VERSION 5.7 ;
BUSBITCHARS "[]" ;
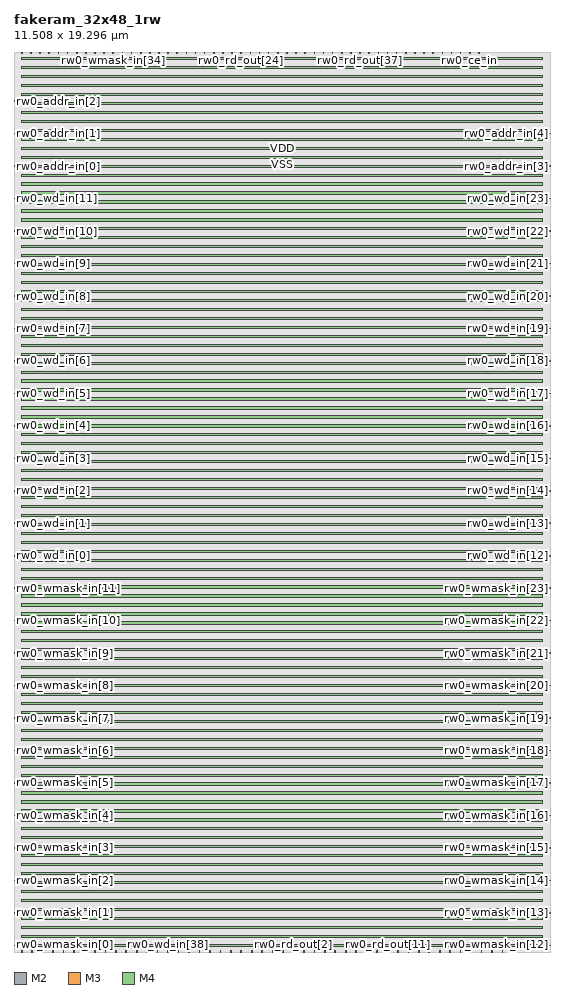
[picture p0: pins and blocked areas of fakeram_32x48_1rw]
MACRO fakeram_32x48_1rw
  FOREIGN fakeram_32x48_1rw 0 0 ;
  SYMMETRY X Y R90 ;
  SIZE 11.508 BY 19.296 ;
  CLASS BLOCK ;
  PIN rw0_wmask_in[0]
    DIRECTION INPUT ;
    USE SIGNAL ;
    SHAPE ABUTMENT ;
    PORT
      LAYER M2 ;
      RECT 0.000 0.138 0.036 0.150 ;
    END
  END rw0_wmask_in[0]
  PIN rw0_wmask_in[1]
    DIRECTION INPUT ;
    USE SIGNAL ;
    SHAPE ABUTMENT ;
    PORT
      LAYER M2 ;
      RECT 0.000 0.834 0.036 0.846 ;
    END
  END rw0_wmask_in[1]
  PIN rw0_wmask_in[2]
    DIRECTION INPUT ;
    USE SIGNAL ;
    SHAPE ABUTMENT ;
    PORT
      LAYER M2 ;
      RECT 0.000 1.530 0.036 1.542 ;
    END
  END rw0_wmask_in[2]
  PIN rw0_wmask_in[3]
    DIRECTION INPUT ;
    USE SIGNAL ;
    SHAPE ABUTMENT ;
    PORT
      LAYER M2 ;
      RECT 0.000 2.226 0.036 2.238 ;
    END
  END rw0_wmask_in[3]
  PIN rw0_wmask_in[4]
    DIRECTION INPUT ;
    USE SIGNAL ;
    SHAPE ABUTMENT ;
    PORT
      LAYER M2 ;
      RECT 0.000 2.922 0.036 2.934 ;
    END
  END rw0_wmask_in[4]
  PIN rw0_wmask_in[5]
    DIRECTION INPUT ;
    USE SIGNAL ;
    SHAPE ABUTMENT ;
    PORT
      LAYER M2 ;
      RECT 0.000 3.618 0.036 3.630 ;
    END
  END rw0_wmask_in[5]
  PIN rw0_wmask_in[6]
    DIRECTION INPUT ;
    USE SIGNAL ;
    SHAPE ABUTMENT ;
    PORT
      LAYER M2 ;
      RECT 0.000 4.314 0.036 4.326 ;
    END
  END rw0_wmask_in[6]
  PIN rw0_wmask_in[7]
    DIRECTION INPUT ;
    USE SIGNAL ;
    SHAPE ABUTMENT ;
    PORT
      LAYER M2 ;
      RECT 0.000 5.010 0.036 5.022 ;
    END
  END rw0_wmask_in[7]
  PIN rw0_wmask_in[8]
    DIRECTION INPUT ;
    USE SIGNAL ;
    SHAPE ABUTMENT ;
    PORT
      LAYER M2 ;
      RECT 0.000 5.706 0.036 5.718 ;
    END
  END rw0_wmask_in[8]
  PIN rw0_wmask_in[9]
    DIRECTION INPUT ;
    USE SIGNAL ;
    SHAPE ABUTMENT ;
    PORT
      LAYER M2 ;
      RECT 0.000 6.402 0.036 6.414 ;
    END
  END rw0_wmask_in[9]
  PIN rw0_wmask_in[10]
    DIRECTION INPUT ;
    USE SIGNAL ;
    SHAPE ABUTMENT ;
    PORT
      LAYER M2 ;
      RECT 0.000 7.098 0.036 7.110 ;
    END
  END rw0_wmask_in[10]
  PIN rw0_wmask_in[11]
    DIRECTION INPUT ;
    USE SIGNAL ;
    SHAPE ABUTMENT ;
    PORT
      LAYER M2 ;
      RECT 0.000 7.794 0.036 7.806 ;
    END
  END rw0_wmask_in[11]
  PIN rw0_wmask_in[12]
    DIRECTION INPUT ;
    USE SIGNAL ;
    SHAPE ABUTMENT ;
    PORT
      LAYER M2 ;
      RECT 11.472 0.138 11.508 0.150 ;
    END
  END rw0_wmask_in[12]
  PIN rw0_wmask_in[13]
    DIRECTION INPUT ;
    USE SIGNAL ;
    SHAPE ABUTMENT ;
    PORT
      LAYER M2 ;
      RECT 11.472 0.834 11.508 0.846 ;
    END
  END rw0_wmask_in[13]
  PIN rw0_wmask_in[14]
    DIRECTION INPUT ;
    USE SIGNAL ;
    SHAPE ABUTMENT ;
    PORT
      LAYER M2 ;
      RECT 11.472 1.530 11.508 1.542 ;
    END
  END rw0_wmask_in[14]
  PIN rw0_wmask_in[15]
    DIRECTION INPUT ;
    USE SIGNAL ;
    SHAPE ABUTMENT ;
    PORT
      LAYER M2 ;
      RECT 11.472 2.226 11.508 2.238 ;
    END
  END rw0_wmask_in[15]
  PIN rw0_wmask_in[16]
    DIRECTION INPUT ;
    USE SIGNAL ;
    SHAPE ABUTMENT ;
    PORT
      LAYER M2 ;
      RECT 11.472 2.922 11.508 2.934 ;
    END
  END rw0_wmask_in[16]
  PIN rw0_wmask_in[17]
    DIRECTION INPUT ;
    USE SIGNAL ;
    SHAPE ABUTMENT ;
    PORT
      LAYER M2 ;
      RECT 11.472 3.618 11.508 3.630 ;
    END
  END rw0_wmask_in[17]
  PIN rw0_wmask_in[18]
    DIRECTION INPUT ;
    USE SIGNAL ;
    SHAPE ABUTMENT ;
    PORT
      LAYER M2 ;
      RECT 11.472 4.314 11.508 4.326 ;
    END
  END rw0_wmask_in[18]
  PIN rw0_wmask_in[19]
    DIRECTION INPUT ;
    USE SIGNAL ;
    SHAPE ABUTMENT ;
    PORT
      LAYER M2 ;
      RECT 11.472 5.010 11.508 5.022 ;
    END
  END rw0_wmask_in[19]
  PIN rw0_wmask_in[20]
    DIRECTION INPUT ;
    USE SIGNAL ;
    SHAPE ABUTMENT ;
    PORT
      LAYER M2 ;
      RECT 11.472 5.706 11.508 5.718 ;
    END
  END rw0_wmask_in[20]
  PIN rw0_wmask_in[21]
    DIRECTION INPUT ;
    USE SIGNAL ;
    SHAPE ABUTMENT ;
    PORT
      LAYER M2 ;
      RECT 11.472 6.402 11.508 6.414 ;
    END
  END rw0_wmask_in[21]
  PIN rw0_wmask_in[22]
    DIRECTION INPUT ;
    USE SIGNAL ;
    SHAPE ABUTMENT ;
    PORT
      LAYER M2 ;
      RECT 11.472 7.098 11.508 7.110 ;
    END
  END rw0_wmask_in[22]
  PIN rw0_wmask_in[23]
    DIRECTION INPUT ;
    USE SIGNAL ;
    SHAPE ABUTMENT ;
    PORT
      LAYER M2 ;
      RECT 11.472 7.794 11.508 7.806 ;
    END
  END rw0_wmask_in[23]
  PIN rw0_wmask_in[24]
    DIRECTION INPUT ;
    USE SIGNAL ;
    SHAPE ABUTMENT ;
    PORT
      LAYER M3 ;
      RECT 0.161 19.254 0.175 19.296 ;
    END
  END rw0_wmask_in[24]
  PIN rw0_wmask_in[25]
    DIRECTION INPUT ;
    USE SIGNAL ;
    SHAPE ABUTMENT ;
    PORT
      LAYER M3 ;
      RECT 0.357 19.254 0.371 19.296 ;
    END
  END rw0_wmask_in[25]
  PIN rw0_wmask_in[26]
    DIRECTION INPUT ;
    USE SIGNAL ;
    SHAPE ABUTMENT ;
    PORT
      LAYER M3 ;
      RECT 0.553 19.254 0.567 19.296 ;
    END
  END rw0_wmask_in[26]
  PIN rw0_wmask_in[27]
    DIRECTION INPUT ;
    USE SIGNAL ;
    SHAPE ABUTMENT ;
    PORT
      LAYER M3 ;
      RECT 0.749 19.254 0.763 19.296 ;
    END
  END rw0_wmask_in[27]
  PIN rw0_wmask_in[28]
    DIRECTION INPUT ;
    USE SIGNAL ;
    SHAPE ABUTMENT ;
    PORT
      LAYER M3 ;
      RECT 0.945 19.254 0.959 19.296 ;
    END
  END rw0_wmask_in[28]
  PIN rw0_wmask_in[29]
    DIRECTION INPUT ;
    USE SIGNAL ;
    SHAPE ABUTMENT ;
    PORT
      LAYER M3 ;
      RECT 1.141 19.254 1.155 19.296 ;
    END
  END rw0_wmask_in[29]
  PIN rw0_wmask_in[30]
    DIRECTION INPUT ;
    USE SIGNAL ;
    SHAPE ABUTMENT ;
    PORT
      LAYER M3 ;
      RECT 1.337 19.254 1.351 19.296 ;
    END
  END rw0_wmask_in[30]
  PIN rw0_wmask_in[31]
    DIRECTION INPUT ;
    USE SIGNAL ;
    SHAPE ABUTMENT ;
    PORT
      LAYER M3 ;
      RECT 1.533 19.254 1.547 19.296 ;
    END
  END rw0_wmask_in[31]
  PIN rw0_wmask_in[32]
    DIRECTION INPUT ;
    USE SIGNAL ;
    SHAPE ABUTMENT ;
    PORT
      LAYER M3 ;
      RECT 1.729 19.254 1.743 19.296 ;
    END
  END rw0_wmask_in[32]
  PIN rw0_wmask_in[33]
    DIRECTION INPUT ;
    USE SIGNAL ;
    SHAPE ABUTMENT ;
    PORT
      LAYER M3 ;
      RECT 1.925 19.254 1.939 19.296 ;
    END
  END rw0_wmask_in[33]
  PIN rw0_wmask_in[34]
    DIRECTION INPUT ;
    USE SIGNAL ;
    SHAPE ABUTMENT ;
    PORT
      LAYER M3 ;
      RECT 2.121 19.254 2.135 19.296 ;
    END
  END rw0_wmask_in[34]
  PIN rw0_wmask_in[35]
    DIRECTION INPUT ;
    USE SIGNAL ;
    SHAPE ABUTMENT ;
    PORT
      LAYER M3 ;
      RECT 2.317 19.254 2.331 19.296 ;
    END
  END rw0_wmask_in[35]
  PIN rw0_wmask_in[36]
    DIRECTION INPUT ;
    USE SIGNAL ;
    SHAPE ABUTMENT ;
    PORT
      LAYER M3 ;
      RECT 2.513 19.254 2.527 19.296 ;
    END
  END rw0_wmask_in[36]
  PIN rw0_wmask_in[37]
    DIRECTION INPUT ;
    USE SIGNAL ;
    SHAPE ABUTMENT ;
    PORT
      LAYER M3 ;
      RECT 2.709 19.254 2.723 19.296 ;
    END
  END rw0_wmask_in[37]
  PIN rw0_wmask_in[38]
    DIRECTION INPUT ;
    USE SIGNAL ;
    SHAPE ABUTMENT ;
    PORT
      LAYER M3 ;
      RECT 2.905 19.254 2.919 19.296 ;
    END
  END rw0_wmask_in[38]
  PIN rw0_wmask_in[39]
    DIRECTION INPUT ;
    USE SIGNAL ;
    SHAPE ABUTMENT ;
    PORT
      LAYER M3 ;
      RECT 3.101 19.254 3.115 19.296 ;
    END
  END rw0_wmask_in[39]
  PIN rw0_wmask_in[40]
    DIRECTION INPUT ;
    USE SIGNAL ;
    SHAPE ABUTMENT ;
    PORT
      LAYER M3 ;
      RECT 3.297 19.254 3.311 19.296 ;
    END
  END rw0_wmask_in[40]
  PIN rw0_wmask_in[41]
    DIRECTION INPUT ;
    USE SIGNAL ;
    SHAPE ABUTMENT ;
    PORT
      LAYER M3 ;
      RECT 3.493 19.254 3.507 19.296 ;
    END
  END rw0_wmask_in[41]
  PIN rw0_wmask_in[42]
    DIRECTION INPUT ;
    USE SIGNAL ;
    SHAPE ABUTMENT ;
    PORT
      LAYER M3 ;
      RECT 3.689 19.254 3.703 19.296 ;
    END
  END rw0_wmask_in[42]
  PIN rw0_wmask_in[43]
    DIRECTION INPUT ;
    USE SIGNAL ;
    SHAPE ABUTMENT ;
    PORT
      LAYER M3 ;
      RECT 3.885 19.254 3.899 19.296 ;
    END
  END rw0_wmask_in[43]
  PIN rw0_wmask_in[44]
    DIRECTION INPUT ;
    USE SIGNAL ;
    SHAPE ABUTMENT ;
    PORT
      LAYER M3 ;
      RECT 4.081 19.254 4.095 19.296 ;
    END
  END rw0_wmask_in[44]
  PIN rw0_wmask_in[45]
    DIRECTION INPUT ;
    USE SIGNAL ;
    SHAPE ABUTMENT ;
    PORT
      LAYER M3 ;
      RECT 4.277 19.254 4.291 19.296 ;
    END
  END rw0_wmask_in[45]
  PIN rw0_wmask_in[46]
    DIRECTION INPUT ;
    USE SIGNAL ;
    SHAPE ABUTMENT ;
    PORT
      LAYER M3 ;
      RECT 4.473 19.254 4.487 19.296 ;
    END
  END rw0_wmask_in[46]
  PIN rw0_wmask_in[47]
    DIRECTION INPUT ;
    USE SIGNAL ;
    SHAPE ABUTMENT ;
    PORT
      LAYER M3 ;
      RECT 4.669 19.254 4.683 19.296 ;
    END
  END rw0_wmask_in[47]
  PIN rw0_wd_in[0]
    DIRECTION INPUT ;
    USE SIGNAL ;
    SHAPE ABUTMENT ;
    PORT
      LAYER M2 ;
      RECT 0.000 8.490 0.036 8.502 ;
    END
  END rw0_wd_in[0]
  PIN rw0_wd_in[1]
    DIRECTION INPUT ;
    USE SIGNAL ;
    SHAPE ABUTMENT ;
    PORT
      LAYER M2 ;
      RECT 0.000 9.186 0.036 9.198 ;
    END
  END rw0_wd_in[1]
  PIN rw0_wd_in[2]
    DIRECTION INPUT ;
    USE SIGNAL ;
    SHAPE ABUTMENT ;
    PORT
      LAYER M2 ;
      RECT 0.000 9.882 0.036 9.894 ;
    END
  END rw0_wd_in[2]
  PIN rw0_wd_in[3]
    DIRECTION INPUT ;
    USE SIGNAL ;
    SHAPE ABUTMENT ;
    PORT
      LAYER M2 ;
      RECT 0.000 10.578 0.036 10.590 ;
    END
  END rw0_wd_in[3]
  PIN rw0_wd_in[4]
    DIRECTION INPUT ;
    USE SIGNAL ;
    SHAPE ABUTMENT ;
    PORT
      LAYER M2 ;
      RECT 0.000 11.274 0.036 11.286 ;
    END
  END rw0_wd_in[4]
  PIN rw0_wd_in[5]
    DIRECTION INPUT ;
    USE SIGNAL ;
    SHAPE ABUTMENT ;
    PORT
      LAYER M2 ;
      RECT 0.000 11.970 0.036 11.982 ;
    END
  END rw0_wd_in[5]
  PIN rw0_wd_in[6]
    DIRECTION INPUT ;
    USE SIGNAL ;
    SHAPE ABUTMENT ;
    PORT
      LAYER M2 ;
      RECT 0.000 12.666 0.036 12.678 ;
    END
  END rw0_wd_in[6]
  PIN rw0_wd_in[7]
    DIRECTION INPUT ;
    USE SIGNAL ;
    SHAPE ABUTMENT ;
    PORT
      LAYER M2 ;
      RECT 0.000 13.362 0.036 13.374 ;
    END
  END rw0_wd_in[7]
  PIN rw0_wd_in[8]
    DIRECTION INPUT ;
    USE SIGNAL ;
    SHAPE ABUTMENT ;
    PORT
      LAYER M2 ;
      RECT 0.000 14.058 0.036 14.070 ;
    END
  END rw0_wd_in[8]
  PIN rw0_wd_in[9]
    DIRECTION INPUT ;
    USE SIGNAL ;
    SHAPE ABUTMENT ;
    PORT
      LAYER M2 ;
      RECT 0.000 14.754 0.036 14.766 ;
    END
  END rw0_wd_in[9]
  PIN rw0_wd_in[10]
    DIRECTION INPUT ;
    USE SIGNAL ;
    SHAPE ABUTMENT ;
    PORT
      LAYER M2 ;
      RECT 0.000 15.450 0.036 15.462 ;
    END
  END rw0_wd_in[10]
  PIN rw0_wd_in[11]
    DIRECTION INPUT ;
    USE SIGNAL ;
    SHAPE ABUTMENT ;
    PORT
      LAYER M2 ;
      RECT 0.000 16.146 0.036 16.158 ;
    END
  END rw0_wd_in[11]
  PIN rw0_wd_in[12]
    DIRECTION INPUT ;
    USE SIGNAL ;
    SHAPE ABUTMENT ;
    PORT
      LAYER M2 ;
      RECT 11.472 8.490 11.508 8.502 ;
    END
  END rw0_wd_in[12]
  PIN rw0_wd_in[13]
    DIRECTION INPUT ;
    USE SIGNAL ;
    SHAPE ABUTMENT ;
    PORT
      LAYER M2 ;
      RECT 11.472 9.186 11.508 9.198 ;
    END
  END rw0_wd_in[13]
  PIN rw0_wd_in[14]
    DIRECTION INPUT ;
    USE SIGNAL ;
    SHAPE ABUTMENT ;
    PORT
      LAYER M2 ;
      RECT 11.472 9.882 11.508 9.894 ;
    END
  END rw0_wd_in[14]
  PIN rw0_wd_in[15]
    DIRECTION INPUT ;
    USE SIGNAL ;
    SHAPE ABUTMENT ;
    PORT
      LAYER M2 ;
      RECT 11.472 10.578 11.508 10.590 ;
    END
  END rw0_wd_in[15]
  PIN rw0_wd_in[16]
    DIRECTION INPUT ;
    USE SIGNAL ;
    SHAPE ABUTMENT ;
    PORT
      LAYER M2 ;
      RECT 11.472 11.274 11.508 11.286 ;
    END
  END rw0_wd_in[16]
  PIN rw0_wd_in[17]
    DIRECTION INPUT ;
    USE SIGNAL ;
    SHAPE ABUTMENT ;
    PORT
      LAYER M2 ;
      RECT 11.472 11.970 11.508 11.982 ;
    END
  END rw0_wd_in[17]
  PIN rw0_wd_in[18]
    DIRECTION INPUT ;
    USE SIGNAL ;
    SHAPE ABUTMENT ;
    PORT
      LAYER M2 ;
      RECT 11.472 12.666 11.508 12.678 ;
    END
  END rw0_wd_in[18]
  PIN rw0_wd_in[19]
    DIRECTION INPUT ;
    USE SIGNAL ;
    SHAPE ABUTMENT ;
    PORT
      LAYER M2 ;
      RECT 11.472 13.362 11.508 13.374 ;
    END
  END rw0_wd_in[19]
  PIN rw0_wd_in[20]
    DIRECTION INPUT ;
    USE SIGNAL ;
    SHAPE ABUTMENT ;
    PORT
      LAYER M2 ;
      RECT 11.472 14.058 11.508 14.070 ;
    END
  END rw0_wd_in[20]
  PIN rw0_wd_in[21]
    DIRECTION INPUT ;
    USE SIGNAL ;
    SHAPE ABUTMENT ;
    PORT
      LAYER M2 ;
      RECT 11.472 14.754 11.508 14.766 ;
    END
  END rw0_wd_in[21]
  PIN rw0_wd_in[22]
    DIRECTION INPUT ;
    USE SIGNAL ;
    SHAPE ABUTMENT ;
    PORT
      LAYER M2 ;
      RECT 11.472 15.450 11.508 15.462 ;
    END
  END rw0_wd_in[22]
  PIN rw0_wd_in[23]
    DIRECTION INPUT ;
    USE SIGNAL ;
    SHAPE ABUTMENT ;
    PORT
      LAYER M2 ;
      RECT 11.472 16.146 11.508 16.158 ;
    END
  END rw0_wd_in[23]
  PIN rw0_wd_in[24]
    DIRECTION INPUT ;
    USE SIGNAL ;
    SHAPE ABUTMENT ;
    PORT
      LAYER M3 ;
      RECT 0.161 0.000 0.175 0.042 ;
    END
  END rw0_wd_in[24]
  PIN rw0_wd_in[25]
    DIRECTION INPUT ;
    USE SIGNAL ;
    SHAPE ABUTMENT ;
    PORT
      LAYER M3 ;
      RECT 0.385 0.000 0.399 0.042 ;
    END
  END rw0_wd_in[25]
  PIN rw0_wd_in[26]
    DIRECTION INPUT ;
    USE SIGNAL ;
    SHAPE ABUTMENT ;
    PORT
      LAYER M3 ;
      RECT 0.609 0.000 0.623 0.042 ;
    END
  END rw0_wd_in[26]
  PIN rw0_wd_in[27]
    DIRECTION INPUT ;
    USE SIGNAL ;
    SHAPE ABUTMENT ;
    PORT
      LAYER M3 ;
      RECT 0.833 0.000 0.847 0.042 ;
    END
  END rw0_wd_in[27]
  PIN rw0_wd_in[28]
    DIRECTION INPUT ;
    USE SIGNAL ;
    SHAPE ABUTMENT ;
    PORT
      LAYER M3 ;
      RECT 1.057 0.000 1.071 0.042 ;
    END
  END rw0_wd_in[28]
  PIN rw0_wd_in[29]
    DIRECTION INPUT ;
    USE SIGNAL ;
    SHAPE ABUTMENT ;
    PORT
      LAYER M3 ;
      RECT 1.281 0.000 1.295 0.042 ;
    END
  END rw0_wd_in[29]
  PIN rw0_wd_in[30]
    DIRECTION INPUT ;
    USE SIGNAL ;
    SHAPE ABUTMENT ;
    PORT
      LAYER M3 ;
      RECT 1.505 0.000 1.519 0.042 ;
    END
  END rw0_wd_in[30]
  PIN rw0_wd_in[31]
    DIRECTION INPUT ;
    USE SIGNAL ;
    SHAPE ABUTMENT ;
    PORT
      LAYER M3 ;
      RECT 1.729 0.000 1.743 0.042 ;
    END
  END rw0_wd_in[31]
  PIN rw0_wd_in[32]
    DIRECTION INPUT ;
    USE SIGNAL ;
    SHAPE ABUTMENT ;
    PORT
      LAYER M3 ;
      RECT 1.953 0.000 1.967 0.042 ;
    END
  END rw0_wd_in[32]
  PIN rw0_wd_in[33]
    DIRECTION INPUT ;
    USE SIGNAL ;
    SHAPE ABUTMENT ;
    PORT
      LAYER M3 ;
      RECT 2.177 0.000 2.191 0.042 ;
    END
  END rw0_wd_in[33]
  PIN rw0_wd_in[34]
    DIRECTION INPUT ;
    USE SIGNAL ;
    SHAPE ABUTMENT ;
    PORT
      LAYER M3 ;
      RECT 2.401 0.000 2.415 0.042 ;
    END
  END rw0_wd_in[34]
  PIN rw0_wd_in[35]
    DIRECTION INPUT ;
    USE SIGNAL ;
    SHAPE ABUTMENT ;
    PORT
      LAYER M3 ;
      RECT 2.625 0.000 2.639 0.042 ;
    END
  END rw0_wd_in[35]
  PIN rw0_wd_in[36]
    DIRECTION INPUT ;
    USE SIGNAL ;
    SHAPE ABUTMENT ;
    PORT
      LAYER M3 ;
      RECT 2.849 0.000 2.863 0.042 ;
    END
  END rw0_wd_in[36]
  PIN rw0_wd_in[37]
    DIRECTION INPUT ;
    USE SIGNAL ;
    SHAPE ABUTMENT ;
    PORT
      LAYER M3 ;
      RECT 3.073 0.000 3.087 0.042 ;
    END
  END rw0_wd_in[37]
  PIN rw0_wd_in[38]
    DIRECTION INPUT ;
    USE SIGNAL ;
    SHAPE ABUTMENT ;
    PORT
      LAYER M3 ;
      RECT 3.297 0.000 3.311 0.042 ;
    END
  END rw0_wd_in[38]
  PIN rw0_wd_in[39]
    DIRECTION INPUT ;
    USE SIGNAL ;
    SHAPE ABUTMENT ;
    PORT
      LAYER M3 ;
      RECT 3.521 0.000 3.535 0.042 ;
    END
  END rw0_wd_in[39]
  PIN rw0_wd_in[40]
    DIRECTION INPUT ;
    USE SIGNAL ;
    SHAPE ABUTMENT ;
    PORT
      LAYER M3 ;
      RECT 3.745 0.000 3.759 0.042 ;
    END
  END rw0_wd_in[40]
  PIN rw0_wd_in[41]
    DIRECTION INPUT ;
    USE SIGNAL ;
    SHAPE ABUTMENT ;
    PORT
      LAYER M3 ;
      RECT 3.969 0.000 3.983 0.042 ;
    END
  END rw0_wd_in[41]
  PIN rw0_wd_in[42]
    DIRECTION INPUT ;
    USE SIGNAL ;
    SHAPE ABUTMENT ;
    PORT
      LAYER M3 ;
      RECT 4.193 0.000 4.207 0.042 ;
    END
  END rw0_wd_in[42]
  PIN rw0_wd_in[43]
    DIRECTION INPUT ;
    USE SIGNAL ;
    SHAPE ABUTMENT ;
    PORT
      LAYER M3 ;
      RECT 4.417 0.000 4.431 0.042 ;
    END
  END rw0_wd_in[43]
  PIN rw0_wd_in[44]
    DIRECTION INPUT ;
    USE SIGNAL ;
    SHAPE ABUTMENT ;
    PORT
      LAYER M3 ;
      RECT 4.641 0.000 4.655 0.042 ;
    END
  END rw0_wd_in[44]
  PIN rw0_wd_in[45]
    DIRECTION INPUT ;
    USE SIGNAL ;
    SHAPE ABUTMENT ;
    PORT
      LAYER M3 ;
      RECT 4.865 0.000 4.879 0.042 ;
    END
  END rw0_wd_in[45]
  PIN rw0_wd_in[46]
    DIRECTION INPUT ;
    USE SIGNAL ;
    SHAPE ABUTMENT ;
    PORT
      LAYER M3 ;
      RECT 5.089 0.000 5.103 0.042 ;
    END
  END rw0_wd_in[46]
  PIN rw0_wd_in[47]
    DIRECTION INPUT ;
    USE SIGNAL ;
    SHAPE ABUTMENT ;
    PORT
      LAYER M3 ;
      RECT 5.313 0.000 5.327 0.042 ;
    END
  END rw0_wd_in[47]
  PIN rw0_rd_out[0]
    DIRECTION OUTPUT ;
    USE SIGNAL ;
    SHAPE ABUTMENT ;
    PORT
      LAYER M3 ;
      RECT 5.537 0.000 5.551 0.042 ;
    END
  END rw0_rd_out[0]
  PIN rw0_rd_out[1]
    DIRECTION OUTPUT ;
    USE SIGNAL ;
    SHAPE ABUTMENT ;
    PORT
      LAYER M3 ;
      RECT 5.761 0.000 5.775 0.042 ;
    END
  END rw0_rd_out[1]
  PIN rw0_rd_out[2]
    DIRECTION OUTPUT ;
    USE SIGNAL ;
    SHAPE ABUTMENT ;
    PORT
      LAYER M3 ;
      RECT 5.985 0.000 5.999 0.042 ;
    END
  END rw0_rd_out[2]
  PIN rw0_rd_out[3]
    DIRECTION OUTPUT ;
    USE SIGNAL ;
    SHAPE ABUTMENT ;
    PORT
      LAYER M3 ;
      RECT 6.209 0.000 6.223 0.042 ;
    END
  END rw0_rd_out[3]
  PIN rw0_rd_out[4]
    DIRECTION OUTPUT ;
    USE SIGNAL ;
    SHAPE ABUTMENT ;
    PORT
      LAYER M3 ;
      RECT 6.433 0.000 6.447 0.042 ;
    END
  END rw0_rd_out[4]
  PIN rw0_rd_out[5]
    DIRECTION OUTPUT ;
    USE SIGNAL ;
    SHAPE ABUTMENT ;
    PORT
      LAYER M3 ;
      RECT 6.657 0.000 6.671 0.042 ;
    END
  END rw0_rd_out[5]
  PIN rw0_rd_out[6]
    DIRECTION OUTPUT ;
    USE SIGNAL ;
    SHAPE ABUTMENT ;
    PORT
      LAYER M3 ;
      RECT 6.881 0.000 6.895 0.042 ;
    END
  END rw0_rd_out[6]
  PIN rw0_rd_out[7]
    DIRECTION OUTPUT ;
    USE SIGNAL ;
    SHAPE ABUTMENT ;
    PORT
      LAYER M3 ;
      RECT 7.105 0.000 7.119 0.042 ;
    END
  END rw0_rd_out[7]
  PIN rw0_rd_out[8]
    DIRECTION OUTPUT ;
    USE SIGNAL ;
    SHAPE ABUTMENT ;
    PORT
      LAYER M3 ;
      RECT 7.329 0.000 7.343 0.042 ;
    END
  END rw0_rd_out[8]
  PIN rw0_rd_out[9]
    DIRECTION OUTPUT ;
    USE SIGNAL ;
    SHAPE ABUTMENT ;
    PORT
      LAYER M3 ;
      RECT 7.553 0.000 7.567 0.042 ;
    END
  END rw0_rd_out[9]
  PIN rw0_rd_out[10]
    DIRECTION OUTPUT ;
    USE SIGNAL ;
    SHAPE ABUTMENT ;
    PORT
      LAYER M3 ;
      RECT 7.777 0.000 7.791 0.042 ;
    END
  END rw0_rd_out[10]
  PIN rw0_rd_out[11]
    DIRECTION OUTPUT ;
    USE SIGNAL ;
    SHAPE ABUTMENT ;
    PORT
      LAYER M3 ;
      RECT 8.001 0.000 8.015 0.042 ;
    END
  END rw0_rd_out[11]
  PIN rw0_rd_out[12]
    DIRECTION OUTPUT ;
    USE SIGNAL ;
    SHAPE ABUTMENT ;
    PORT
      LAYER M3 ;
      RECT 8.225 0.000 8.239 0.042 ;
    END
  END rw0_rd_out[12]
  PIN rw0_rd_out[13]
    DIRECTION OUTPUT ;
    USE SIGNAL ;
    SHAPE ABUTMENT ;
    PORT
      LAYER M3 ;
      RECT 8.449 0.000 8.463 0.042 ;
    END
  END rw0_rd_out[13]
  PIN rw0_rd_out[14]
    DIRECTION OUTPUT ;
    USE SIGNAL ;
    SHAPE ABUTMENT ;
    PORT
      LAYER M3 ;
      RECT 8.673 0.000 8.687 0.042 ;
    END
  END rw0_rd_out[14]
  PIN rw0_rd_out[15]
    DIRECTION OUTPUT ;
    USE SIGNAL ;
    SHAPE ABUTMENT ;
    PORT
      LAYER M3 ;
      RECT 8.897 0.000 8.911 0.042 ;
    END
  END rw0_rd_out[15]
  PIN rw0_rd_out[16]
    DIRECTION OUTPUT ;
    USE SIGNAL ;
    SHAPE ABUTMENT ;
    PORT
      LAYER M3 ;
      RECT 9.121 0.000 9.135 0.042 ;
    END
  END rw0_rd_out[16]
  PIN rw0_rd_out[17]
    DIRECTION OUTPUT ;
    USE SIGNAL ;
    SHAPE ABUTMENT ;
    PORT
      LAYER M3 ;
      RECT 9.345 0.000 9.359 0.042 ;
    END
  END rw0_rd_out[17]
  PIN rw0_rd_out[18]
    DIRECTION OUTPUT ;
    USE SIGNAL ;
    SHAPE ABUTMENT ;
    PORT
      LAYER M3 ;
      RECT 9.569 0.000 9.583 0.042 ;
    END
  END rw0_rd_out[18]
  PIN rw0_rd_out[19]
    DIRECTION OUTPUT ;
    USE SIGNAL ;
    SHAPE ABUTMENT ;
    PORT
      LAYER M3 ;
      RECT 9.793 0.000 9.807 0.042 ;
    END
  END rw0_rd_out[19]
  PIN rw0_rd_out[20]
    DIRECTION OUTPUT ;
    USE SIGNAL ;
    SHAPE ABUTMENT ;
    PORT
      LAYER M3 ;
      RECT 10.017 0.000 10.031 0.042 ;
    END
  END rw0_rd_out[20]
  PIN rw0_rd_out[21]
    DIRECTION OUTPUT ;
    USE SIGNAL ;
    SHAPE ABUTMENT ;
    PORT
      LAYER M3 ;
      RECT 10.241 0.000 10.255 0.042 ;
    END
  END rw0_rd_out[21]
  PIN rw0_rd_out[22]
    DIRECTION OUTPUT ;
    USE SIGNAL ;
    SHAPE ABUTMENT ;
    PORT
      LAYER M3 ;
      RECT 10.465 0.000 10.479 0.042 ;
    END
  END rw0_rd_out[22]
  PIN rw0_rd_out[23]
    DIRECTION OUTPUT ;
    USE SIGNAL ;
    SHAPE ABUTMENT ;
    PORT
      LAYER M3 ;
      RECT 10.689 0.000 10.703 0.042 ;
    END
  END rw0_rd_out[23]
  PIN rw0_rd_out[24]
    DIRECTION OUTPUT ;
    USE SIGNAL ;
    SHAPE ABUTMENT ;
    PORT
      LAYER M3 ;
      RECT 4.865 19.254 4.879 19.296 ;
    END
  END rw0_rd_out[24]
  PIN rw0_rd_out[25]
    DIRECTION OUTPUT ;
    USE SIGNAL ;
    SHAPE ABUTMENT ;
    PORT
      LAYER M3 ;
      RECT 5.061 19.254 5.075 19.296 ;
    END
  END rw0_rd_out[25]
  PIN rw0_rd_out[26]
    DIRECTION OUTPUT ;
    USE SIGNAL ;
    SHAPE ABUTMENT ;
    PORT
      LAYER M3 ;
      RECT 5.257 19.254 5.271 19.296 ;
    END
  END rw0_rd_out[26]
  PIN rw0_rd_out[27]
    DIRECTION OUTPUT ;
    USE SIGNAL ;
    SHAPE ABUTMENT ;
    PORT
      LAYER M3 ;
      RECT 5.453 19.254 5.467 19.296 ;
    END
  END rw0_rd_out[27]
  PIN rw0_rd_out[28]
    DIRECTION OUTPUT ;
    USE SIGNAL ;
    SHAPE ABUTMENT ;
    PORT
      LAYER M3 ;
      RECT 5.649 19.254 5.663 19.296 ;
    END
  END rw0_rd_out[28]
  PIN rw0_rd_out[29]
    DIRECTION OUTPUT ;
    USE SIGNAL ;
    SHAPE ABUTMENT ;
    PORT
      LAYER M3 ;
      RECT 5.845 19.254 5.859 19.296 ;
    END
  END rw0_rd_out[29]
  PIN rw0_rd_out[30]
    DIRECTION OUTPUT ;
    USE SIGNAL ;
    SHAPE ABUTMENT ;
    PORT
      LAYER M3 ;
      RECT 6.041 19.254 6.055 19.296 ;
    END
  END rw0_rd_out[30]
  PIN rw0_rd_out[31]
    DIRECTION OUTPUT ;
    USE SIGNAL ;
    SHAPE ABUTMENT ;
    PORT
      LAYER M3 ;
      RECT 6.237 19.254 6.251 19.296 ;
    END
  END rw0_rd_out[31]
  PIN rw0_rd_out[32]
    DIRECTION OUTPUT ;
    USE SIGNAL ;
    SHAPE ABUTMENT ;
    PORT
      LAYER M3 ;
      RECT 6.433 19.254 6.447 19.296 ;
    END
  END rw0_rd_out[32]
  PIN rw0_rd_out[33]
    DIRECTION OUTPUT ;
    USE SIGNAL ;
    SHAPE ABUTMENT ;
    PORT
      LAYER M3 ;
      RECT 6.629 19.254 6.643 19.296 ;
    END
  END rw0_rd_out[33]
  PIN rw0_rd_out[34]
    DIRECTION OUTPUT ;
    USE SIGNAL ;
    SHAPE ABUTMENT ;
    PORT
      LAYER M3 ;
      RECT 6.825 19.254 6.839 19.296 ;
    END
  END rw0_rd_out[34]
  PIN rw0_rd_out[35]
    DIRECTION OUTPUT ;
    USE SIGNAL ;
    SHAPE ABUTMENT ;
    PORT
      LAYER M3 ;
      RECT 7.021 19.254 7.035 19.296 ;
    END
  END rw0_rd_out[35]
  PIN rw0_rd_out[36]
    DIRECTION OUTPUT ;
    USE SIGNAL ;
    SHAPE ABUTMENT ;
    PORT
      LAYER M3 ;
      RECT 7.217 19.254 7.231 19.296 ;
    END
  END rw0_rd_out[36]
  PIN rw0_rd_out[37]
    DIRECTION OUTPUT ;
    USE SIGNAL ;
    SHAPE ABUTMENT ;
    PORT
      LAYER M3 ;
      RECT 7.413 19.254 7.427 19.296 ;
    END
  END rw0_rd_out[37]
  PIN rw0_rd_out[38]
    DIRECTION OUTPUT ;
    USE SIGNAL ;
    SHAPE ABUTMENT ;
    PORT
      LAYER M3 ;
      RECT 7.609 19.254 7.623 19.296 ;
    END
  END rw0_rd_out[38]
  PIN rw0_rd_out[39]
    DIRECTION OUTPUT ;
    USE SIGNAL ;
    SHAPE ABUTMENT ;
    PORT
      LAYER M3 ;
      RECT 7.805 19.254 7.819 19.296 ;
    END
  END rw0_rd_out[39]
  PIN rw0_rd_out[40]
    DIRECTION OUTPUT ;
    USE SIGNAL ;
    SHAPE ABUTMENT ;
    PORT
      LAYER M3 ;
      RECT 8.001 19.254 8.015 19.296 ;
    END
  END rw0_rd_out[40]
  PIN rw0_rd_out[41]
    DIRECTION OUTPUT ;
    USE SIGNAL ;
    SHAPE ABUTMENT ;
    PORT
      LAYER M3 ;
      RECT 8.197 19.254 8.211 19.296 ;
    END
  END rw0_rd_out[41]
  PIN rw0_rd_out[42]
    DIRECTION OUTPUT ;
    USE SIGNAL ;
    SHAPE ABUTMENT ;
    PORT
      LAYER M3 ;
      RECT 8.393 19.254 8.407 19.296 ;
    END
  END rw0_rd_out[42]
  PIN rw0_rd_out[43]
    DIRECTION OUTPUT ;
    USE SIGNAL ;
    SHAPE ABUTMENT ;
    PORT
      LAYER M3 ;
      RECT 8.589 19.254 8.603 19.296 ;
    END
  END rw0_rd_out[43]
  PIN rw0_rd_out[44]
    DIRECTION OUTPUT ;
    USE SIGNAL ;
    SHAPE ABUTMENT ;
    PORT
      LAYER M3 ;
      RECT 8.785 19.254 8.799 19.296 ;
    END
  END rw0_rd_out[44]
  PIN rw0_rd_out[45]
    DIRECTION OUTPUT ;
    USE SIGNAL ;
    SHAPE ABUTMENT ;
    PORT
      LAYER M3 ;
      RECT 8.981 19.254 8.995 19.296 ;
    END
  END rw0_rd_out[45]
  PIN rw0_rd_out[46]
    DIRECTION OUTPUT ;
    USE SIGNAL ;
    SHAPE ABUTMENT ;
    PORT
      LAYER M3 ;
      RECT 9.177 19.254 9.191 19.296 ;
    END
  END rw0_rd_out[46]
  PIN rw0_rd_out[47]
    DIRECTION OUTPUT ;
    USE SIGNAL ;
    SHAPE ABUTMENT ;
    PORT
      LAYER M3 ;
      RECT 9.373 19.254 9.387 19.296 ;
    END
  END rw0_rd_out[47]
  PIN rw0_addr_in[0]
    DIRECTION INPUT ;
    USE SIGNAL ;
    SHAPE ABUTMENT ;
    PORT
      LAYER M2 ;
      RECT 0.000 16.842 0.036 16.854 ;
    END
  END rw0_addr_in[0]
  PIN rw0_addr_in[1]
    DIRECTION INPUT ;
    USE SIGNAL ;
    SHAPE ABUTMENT ;
    PORT
      LAYER M2 ;
      RECT 0.000 17.538 0.036 17.550 ;
    END
  END rw0_addr_in[1]
  PIN rw0_addr_in[2]
    DIRECTION INPUT ;
    USE SIGNAL ;
    SHAPE ABUTMENT ;
    PORT
      LAYER M2 ;
      RECT 0.000 18.234 0.036 18.246 ;
    END
  END rw0_addr_in[2]
  PIN rw0_addr_in[3]
    DIRECTION INPUT ;
    USE SIGNAL ;
    SHAPE ABUTMENT ;
    PORT
      LAYER M2 ;
      RECT 11.472 16.842 11.508 16.854 ;
    END
  END rw0_addr_in[3]
  PIN rw0_addr_in[4]
    DIRECTION INPUT ;
    USE SIGNAL ;
    SHAPE ABUTMENT ;
    PORT
      LAYER M2 ;
      RECT 11.472 17.538 11.508 17.550 ;
    END
  END rw0_addr_in[4]
  PIN rw0_we_in
    DIRECTION INPUT ;
    USE SIGNAL ;
    SHAPE ABUTMENT ;
    PORT
      LAYER M3 ;
      RECT 9.569 19.254 9.583 19.296 ;
    END
  END rw0_we_in
  PIN rw0_ce_in
    DIRECTION INPUT ;
    USE SIGNAL ;
    SHAPE ABUTMENT ;
    PORT
      LAYER M3 ;
      RECT 9.765 19.254 9.779 19.296 ;
    END
  END rw0_ce_in
  PIN rw0_clk
    DIRECTION INPUT ;
    USE SIGNAL ;
    SHAPE ABUTMENT ;
    PORT
      LAYER M3 ;
      RECT 9.961 19.254 9.975 19.296 ;
    END
  END rw0_clk
  PIN VSS
    DIRECTION INOUT ;
    USE GROUND ;
    PORT
      LAYER M4 ;
      RECT 0.168 0.120 11.340 0.168 ;
      RECT 0.168 0.504 11.340 0.552 ;
      RECT 0.168 0.888 11.340 0.936 ;
      RECT 0.168 1.272 11.340 1.320 ;
      RECT 0.168 1.656 11.340 1.704 ;
      RECT 0.168 2.040 11.340 2.088 ;
      RECT 0.168 2.424 11.340 2.472 ;
      RECT 0.168 2.808 11.340 2.856 ;
      RECT 0.168 3.192 11.340 3.240 ;
      RECT 0.168 3.576 11.340 3.624 ;
      RECT 0.168 3.960 11.340 4.008 ;
      RECT 0.168 4.344 11.340 4.392 ;
      RECT 0.168 4.728 11.340 4.776 ;
      RECT 0.168 5.112 11.340 5.160 ;
      RECT 0.168 5.496 11.340 5.544 ;
      RECT 0.168 5.880 11.340 5.928 ;
      RECT 0.168 6.264 11.340 6.312 ;
      RECT 0.168 6.648 11.340 6.696 ;
      RECT 0.168 7.032 11.340 7.080 ;
      RECT 0.168 7.416 11.340 7.464 ;
      RECT 0.168 7.800 11.340 7.848 ;
      RECT 0.168 8.184 11.340 8.232 ;
      RECT 0.168 8.568 11.340 8.616 ;
      RECT 0.168 8.952 11.340 9.000 ;
      RECT 0.168 9.336 11.340 9.384 ;
      RECT 0.168 9.720 11.340 9.768 ;
      RECT 0.168 10.104 11.340 10.152 ;
      RECT 0.168 10.488 11.340 10.536 ;
      RECT 0.168 10.872 11.340 10.920 ;
      RECT 0.168 11.256 11.340 11.304 ;
      RECT 0.168 11.640 11.340 11.688 ;
      RECT 0.168 12.024 11.340 12.072 ;
      RECT 0.168 12.408 11.340 12.456 ;
      RECT 0.168 12.792 11.340 12.840 ;
      RECT 0.168 13.176 11.340 13.224 ;
      RECT 0.168 13.560 11.340 13.608 ;
      RECT 0.168 13.944 11.340 13.992 ;
      RECT 0.168 14.328 11.340 14.376 ;
      RECT 0.168 14.712 11.340 14.760 ;
      RECT 0.168 15.096 11.340 15.144 ;
      RECT 0.168 15.480 11.340 15.528 ;
      RECT 0.168 15.864 11.340 15.912 ;
      RECT 0.168 16.248 11.340 16.296 ;
      RECT 0.168 16.632 11.340 16.680 ;
      RECT 0.168 17.016 11.340 17.064 ;
      RECT 0.168 17.400 11.340 17.448 ;
      RECT 0.168 17.784 11.340 17.832 ;
      RECT 0.168 18.168 11.340 18.216 ;
      RECT 0.168 18.552 11.340 18.600 ;
      RECT 0.168 18.936 11.340 18.984 ;
    END
  END VSS
  PIN VDD
    DIRECTION INOUT ;
    USE POWER ;
    PORT
      LAYER M4 ;
      RECT 0.168 0.312 11.340 0.360 ;
      RECT 0.168 0.696 11.340 0.744 ;
      RECT 0.168 1.080 11.340 1.128 ;
      RECT 0.168 1.464 11.340 1.512 ;
      RECT 0.168 1.848 11.340 1.896 ;
      RECT 0.168 2.232 11.340 2.280 ;
      RECT 0.168 2.616 11.340 2.664 ;
      RECT 0.168 3.000 11.340 3.048 ;
      RECT 0.168 3.384 11.340 3.432 ;
      RECT 0.168 3.768 11.340 3.816 ;
      RECT 0.168 4.152 11.340 4.200 ;
      RECT 0.168 4.536 11.340 4.584 ;
      RECT 0.168 4.920 11.340 4.968 ;
      RECT 0.168 5.304 11.340 5.352 ;
      RECT 0.168 5.688 11.340 5.736 ;
      RECT 0.168 6.072 11.340 6.120 ;
      RECT 0.168 6.456 11.340 6.504 ;
      RECT 0.168 6.840 11.340 6.888 ;
      RECT 0.168 7.224 11.340 7.272 ;
      RECT 0.168 7.608 11.340 7.656 ;
      RECT 0.168 7.992 11.340 8.040 ;
      RECT 0.168 8.376 11.340 8.424 ;
      RECT 0.168 8.760 11.340 8.808 ;
      RECT 0.168 9.144 11.340 9.192 ;
      RECT 0.168 9.528 11.340 9.576 ;
      RECT 0.168 9.912 11.340 9.960 ;
      RECT 0.168 10.296 11.340 10.344 ;
      RECT 0.168 10.680 11.340 10.728 ;
      RECT 0.168 11.064 11.340 11.112 ;
      RECT 0.168 11.448 11.340 11.496 ;
      RECT 0.168 11.832 11.340 11.880 ;
      RECT 0.168 12.216 11.340 12.264 ;
      RECT 0.168 12.600 11.340 12.648 ;
      RECT 0.168 12.984 11.340 13.032 ;
      RECT 0.168 13.368 11.340 13.416 ;
      RECT 0.168 13.752 11.340 13.800 ;
      RECT 0.168 14.136 11.340 14.184 ;
      RECT 0.168 14.520 11.340 14.568 ;
      RECT 0.168 14.904 11.340 14.952 ;
      RECT 0.168 15.288 11.340 15.336 ;
      RECT 0.168 15.672 11.340 15.720 ;
      RECT 0.168 16.056 11.340 16.104 ;
      RECT 0.168 16.440 11.340 16.488 ;
      RECT 0.168 16.824 11.340 16.872 ;
      RECT 0.168 17.208 11.340 17.256 ;
      RECT 0.168 17.592 11.340 17.640 ;
      RECT 0.168 17.976 11.340 18.024 ;
      RECT 0.168 18.360 11.340 18.408 ;
      RECT 0.168 18.744 11.340 18.792 ;
      RECT 0.168 19.128 11.340 19.176 ;
    END
  END VDD
  OBS
    LAYER M1 ;
    RECT 0 0 11.508 19.296 ;
    LAYER M2 ;
    RECT 0 0 11.508 19.296 ;
    LAYER M3 ;
    RECT 0 0 11.508 19.296 ;
    LAYER M4 ;
    RECT 0 0 11.508 19.296 ;
  END
END fakeram_32x48_1rw

END LIBRARY
